VERSION 5.7 ;
  NOWIREEXTENSIONATPIN ON ;
  DIVIDERCHAR "/" ;
  BUSBITCHARS "[]" ;
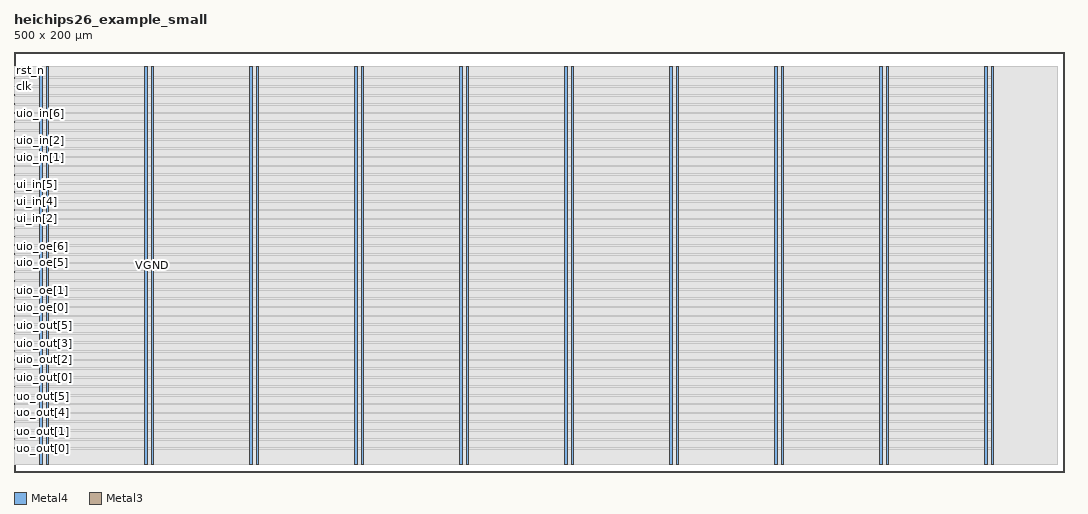
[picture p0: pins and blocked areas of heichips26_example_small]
MACRO heichips26_example_small
  CLASS BLOCK ;
  FOREIGN heichips26_example_small ;
  ORIGIN 0.000 0.000 ;
  SIZE 500.000 BY 200.000 ;
  PIN VGND
    DIRECTION INOUT ;
    USE GROUND ;
    PORT
      LAYER Metal4 ;
        RECT 15.380 3.560 16.380 193.000 ;
    END
    PORT
      LAYER Metal4 ;
        RECT 65.380 3.560 66.380 193.000 ;
    END
    PORT
      LAYER Metal4 ;
        RECT 115.380 3.560 116.380 193.000 ;
    END
    PORT
      LAYER Metal4 ;
        RECT 165.380 3.560 166.380 193.000 ;
    END
    PORT
      LAYER Metal4 ;
        RECT 215.380 3.560 216.380 193.000 ;
    END
    PORT
      LAYER Metal4 ;
        RECT 265.380 3.560 266.380 193.000 ;
    END
    PORT
      LAYER Metal4 ;
        RECT 315.380 3.560 316.380 193.000 ;
    END
    PORT
      LAYER Metal4 ;
        RECT 365.380 3.560 366.380 193.000 ;
    END
    PORT
      LAYER Metal4 ;
        RECT 415.380 3.560 416.380 193.000 ;
    END
    PORT
      LAYER Metal4 ;
        RECT 465.380 3.560 466.380 193.000 ;
    END
  END VGND
  PIN VPWR
    DIRECTION INOUT ;
    USE POWER ;
    PORT
      LAYER Metal4 ;
        RECT 12.380 3.560 13.380 193.000 ;
    END
    PORT
      LAYER Metal4 ;
        RECT 62.380 3.560 63.380 193.000 ;
    END
    PORT
      LAYER Metal4 ;
        RECT 112.380 3.560 113.380 193.000 ;
    END
    PORT
      LAYER Metal4 ;
        RECT 162.380 3.560 163.380 193.000 ;
    END
    PORT
      LAYER Metal4 ;
        RECT 212.380 3.560 213.380 193.000 ;
    END
    PORT
      LAYER Metal4 ;
        RECT 262.380 3.560 263.380 193.000 ;
    END
    PORT
      LAYER Metal4 ;
        RECT 312.380 3.560 313.380 193.000 ;
    END
    PORT
      LAYER Metal4 ;
        RECT 362.380 3.560 363.380 193.000 ;
    END
    PORT
      LAYER Metal4 ;
        RECT 412.380 3.560 413.380 193.000 ;
    END
    PORT
      LAYER Metal4 ;
        RECT 462.380 3.560 463.380 193.000 ;
    END
  END VPWR
  PIN clk
    DIRECTION INPUT ;
    USE SIGNAL ;
    PORT
      LAYER Metal3 ;
        RECT 0.000 183.340 0.400 183.740 ;
    END
  END clk
  PIN ena
    DIRECTION INPUT ;
    USE SIGNAL ;
    PORT
      LAYER Metal3 ;
        RECT 0.000 179.140 0.400 179.540 ;
    END
  END ena
  PIN rst_n
    DIRECTION INPUT ;
    USE SIGNAL ;
    PORT
      LAYER Metal3 ;
        RECT 0.000 187.540 0.400 187.940 ;
    END
  END rst_n
  PIN ui_in[0]
    DIRECTION INPUT ;
    USE SIGNAL ;
    ANTENNAGATEAREA 0.180700 ;
    PORT
      LAYER Metal3 ;
        RECT 0.000 111.940 0.400 112.340 ;
    END
  END ui_in[0]
  PIN ui_in[1]
    DIRECTION INPUT ;
    USE SIGNAL ;
    ANTENNAGATEAREA 0.180700 ;
    PORT
      LAYER Metal3 ;
        RECT 0.000 116.140 0.400 116.540 ;
    END
  END ui_in[1]
  PIN ui_in[2]
    DIRECTION INPUT ;
    USE SIGNAL ;
    ANTENNAGATEAREA 0.180700 ;
    PORT
      LAYER Metal3 ;
        RECT 0.000 120.340 0.400 120.740 ;
    END
  END ui_in[2]
  PIN ui_in[3]
    DIRECTION INPUT ;
    USE SIGNAL ;
    ANTENNAGATEAREA 0.180700 ;
    PORT
      LAYER Metal3 ;
        RECT 0.000 124.540 0.400 124.940 ;
    END
  END ui_in[3]
  PIN ui_in[4]
    DIRECTION INPUT ;
    USE SIGNAL ;
    ANTENNAGATEAREA 0.180700 ;
    PORT
      LAYER Metal3 ;
        RECT 0.000 128.740 0.400 129.140 ;
    END
  END ui_in[4]
  PIN ui_in[5]
    DIRECTION INPUT ;
    USE SIGNAL ;
    ANTENNAGATEAREA 0.180700 ;
    PORT
      LAYER Metal3 ;
        RECT 0.000 132.940 0.400 133.340 ;
    END
  END ui_in[5]
  PIN ui_in[6]
    DIRECTION INPUT ;
    USE SIGNAL ;
    ANTENNAGATEAREA 0.180700 ;
    PORT
      LAYER Metal3 ;
        RECT 0.000 137.140 0.400 137.540 ;
    END
  END ui_in[6]
  PIN ui_in[7]
    DIRECTION INPUT ;
    USE SIGNAL ;
    ANTENNAGATEAREA 0.180700 ;
    PORT
      LAYER Metal3 ;
        RECT 0.000 141.340 0.400 141.740 ;
    END
  END ui_in[7]
  PIN uio_in[0]
    DIRECTION INPUT ;
    USE SIGNAL ;
    ANTENNAGATEAREA 0.180700 ;
    PORT
      LAYER Metal3 ;
        RECT 0.000 145.540 0.400 145.940 ;
    END
  END uio_in[0]
  PIN uio_in[1]
    DIRECTION INPUT ;
    USE SIGNAL ;
    ANTENNAGATEAREA 0.180700 ;
    PORT
      LAYER Metal3 ;
        RECT 0.000 149.740 0.400 150.140 ;
    END
  END uio_in[1]
  PIN uio_in[2]
    DIRECTION INPUT ;
    USE SIGNAL ;
    ANTENNAGATEAREA 0.180700 ;
    PORT
      LAYER Metal3 ;
        RECT 0.000 153.940 0.400 154.340 ;
    END
  END uio_in[2]
  PIN uio_in[3]
    DIRECTION INPUT ;
    USE SIGNAL ;
    ANTENNAGATEAREA 0.180700 ;
    PORT
      LAYER Metal3 ;
        RECT 0.000 158.140 0.400 158.540 ;
    END
  END uio_in[3]
  PIN uio_in[4]
    DIRECTION INPUT ;
    USE SIGNAL ;
    ANTENNAGATEAREA 0.180700 ;
    PORT
      LAYER Metal3 ;
        RECT 0.000 162.340 0.400 162.740 ;
    END
  END uio_in[4]
  PIN uio_in[5]
    DIRECTION INPUT ;
    USE SIGNAL ;
    ANTENNAGATEAREA 0.180700 ;
    PORT
      LAYER Metal3 ;
        RECT 0.000 166.540 0.400 166.940 ;
    END
  END uio_in[5]
  PIN uio_in[6]
    DIRECTION INPUT ;
    USE SIGNAL ;
    ANTENNAGATEAREA 0.180700 ;
    PORT
      LAYER Metal3 ;
        RECT 0.000 170.740 0.400 171.140 ;
    END
  END uio_in[6]
  PIN uio_in[7]
    DIRECTION INPUT ;
    USE SIGNAL ;
    ANTENNAGATEAREA 0.180700 ;
    PORT
      LAYER Metal3 ;
        RECT 0.000 174.940 0.400 175.340 ;
    END
  END uio_in[7]
  PIN uio_oe[0]
    DIRECTION OUTPUT ;
    USE SIGNAL ;
    ANTENNADIFFAREA 0.299200 ;
    PORT
      LAYER Metal3 ;
        RECT 0.000 78.340 0.400 78.740 ;
    END
  END uio_oe[0]
  PIN uio_oe[1]
    DIRECTION OUTPUT ;
    USE SIGNAL ;
    ANTENNADIFFAREA 0.299200 ;
    PORT
      LAYER Metal3 ;
        RECT 0.000 82.540 0.400 82.940 ;
    END
  END uio_oe[1]
  PIN uio_oe[2]
    DIRECTION OUTPUT ;
    USE SIGNAL ;
    ANTENNADIFFAREA 0.299200 ;
    PORT
      LAYER Metal3 ;
        RECT 0.000 86.740 0.400 87.140 ;
    END
  END uio_oe[2]
  PIN uio_oe[3]
    DIRECTION OUTPUT ;
    USE SIGNAL ;
    ANTENNADIFFAREA 0.299200 ;
    PORT
      LAYER Metal3 ;
        RECT 0.000 90.940 0.400 91.340 ;
    END
  END uio_oe[3]
  PIN uio_oe[4]
    DIRECTION OUTPUT ;
    USE SIGNAL ;
    ANTENNADIFFAREA 0.299200 ;
    PORT
      LAYER Metal3 ;
        RECT 0.000 95.140 0.400 95.540 ;
    END
  END uio_oe[4]
  PIN uio_oe[5]
    DIRECTION OUTPUT ;
    USE SIGNAL ;
    ANTENNADIFFAREA 0.299200 ;
    PORT
      LAYER Metal3 ;
        RECT 0.000 99.340 0.400 99.740 ;
    END
  END uio_oe[5]
  PIN uio_oe[6]
    DIRECTION OUTPUT ;
    USE SIGNAL ;
    ANTENNADIFFAREA 0.299200 ;
    PORT
      LAYER Metal3 ;
        RECT 0.000 103.540 0.400 103.940 ;
    END
  END uio_oe[6]
  PIN uio_oe[7]
    DIRECTION OUTPUT ;
    USE SIGNAL ;
    ANTENNADIFFAREA 0.299200 ;
    PORT
      LAYER Metal3 ;
        RECT 0.000 107.740 0.400 108.140 ;
    END
  END uio_oe[7]
  PIN uio_out[0]
    DIRECTION OUTPUT ;
    USE SIGNAL ;
    ANTENNADIFFAREA 0.299200 ;
    PORT
      LAYER Metal3 ;
        RECT 0.000 44.740 0.400 45.140 ;
    END
  END uio_out[0]
  PIN uio_out[1]
    DIRECTION OUTPUT ;
    USE SIGNAL ;
    ANTENNADIFFAREA 0.299200 ;
    PORT
      LAYER Metal3 ;
        RECT 0.000 48.940 0.400 49.340 ;
    END
  END uio_out[1]
  PIN uio_out[2]
    DIRECTION OUTPUT ;
    USE SIGNAL ;
    ANTENNADIFFAREA 0.299200 ;
    PORT
      LAYER Metal3 ;
        RECT 0.000 53.140 0.400 53.540 ;
    END
  END uio_out[2]
  PIN uio_out[3]
    DIRECTION OUTPUT ;
    USE SIGNAL ;
    ANTENNADIFFAREA 0.299200 ;
    PORT
      LAYER Metal3 ;
        RECT 0.000 57.340 0.400 57.740 ;
    END
  END uio_out[3]
  PIN uio_out[4]
    DIRECTION OUTPUT ;
    USE SIGNAL ;
    ANTENNADIFFAREA 0.299200 ;
    PORT
      LAYER Metal3 ;
        RECT 0.000 61.540 0.400 61.940 ;
    END
  END uio_out[4]
  PIN uio_out[5]
    DIRECTION OUTPUT ;
    USE SIGNAL ;
    ANTENNADIFFAREA 0.299200 ;
    PORT
      LAYER Metal3 ;
        RECT 0.000 65.740 0.400 66.140 ;
    END
  END uio_out[5]
  PIN uio_out[6]
    DIRECTION OUTPUT ;
    USE SIGNAL ;
    ANTENNADIFFAREA 0.299200 ;
    PORT
      LAYER Metal3 ;
        RECT 0.000 69.940 0.400 70.340 ;
    END
  END uio_out[6]
  PIN uio_out[7]
    DIRECTION OUTPUT ;
    USE SIGNAL ;
    ANTENNADIFFAREA 0.299200 ;
    PORT
      LAYER Metal3 ;
        RECT 0.000 74.140 0.400 74.540 ;
    END
  END uio_out[7]
  PIN uo_out[0]
    DIRECTION OUTPUT ;
    USE SIGNAL ;
    ANTENNADIFFAREA 0.708600 ;
    PORT
      LAYER Metal3 ;
        RECT 0.000 11.140 0.400 11.540 ;
    END
  END uo_out[0]
  PIN uo_out[1]
    DIRECTION OUTPUT ;
    USE SIGNAL ;
    ANTENNADIFFAREA 0.708600 ;
    PORT
      LAYER Metal3 ;
        RECT 0.000 15.340 0.400 15.740 ;
    END
  END uo_out[1]
  PIN uo_out[2]
    DIRECTION OUTPUT ;
    USE SIGNAL ;
    ANTENNADIFFAREA 0.708600 ;
    PORT
      LAYER Metal3 ;
        RECT 0.000 19.540 0.400 19.940 ;
    END
  END uo_out[2]
  PIN uo_out[3]
    DIRECTION OUTPUT ;
    USE SIGNAL ;
    ANTENNADIFFAREA 0.708600 ;
    PORT
      LAYER Metal3 ;
        RECT 0.000 23.740 0.400 24.140 ;
    END
  END uo_out[3]
  PIN uo_out[4]
    DIRECTION OUTPUT ;
    USE SIGNAL ;
    ANTENNADIFFAREA 0.708600 ;
    PORT
      LAYER Metal3 ;
        RECT 0.000 27.940 0.400 28.340 ;
    END
  END uo_out[4]
  PIN uo_out[5]
    DIRECTION OUTPUT ;
    USE SIGNAL ;
    ANTENNADIFFAREA 0.708600 ;
    PORT
      LAYER Metal3 ;
        RECT 0.000 32.140 0.400 32.540 ;
    END
  END uo_out[5]
  PIN uo_out[6]
    DIRECTION OUTPUT ;
    USE SIGNAL ;
    ANTENNADIFFAREA 0.708600 ;
    PORT
      LAYER Metal3 ;
        RECT 0.000 36.340 0.400 36.740 ;
    END
  END uo_out[6]
  PIN uo_out[7]
    DIRECTION OUTPUT ;
    USE SIGNAL ;
    ANTENNADIFFAREA 0.708600 ;
    PORT
      LAYER Metal3 ;
        RECT 0.000 40.540 0.400 40.940 ;
    END
  END uo_out[7]
  OBS
      LAYER GatPoly ;
        RECT 2.880 3.630 496.800 192.930 ;
      LAYER Metal1 ;
        RECT 2.880 3.560 496.800 193.000 ;
      LAYER Metal2 ;
        RECT 2.295 3.635 466.185 192.925 ;
      LAYER Metal3 ;
        RECT 0.400 188.150 466.240 192.880 ;
        RECT 0.610 187.330 466.240 188.150 ;
        RECT 0.400 183.950 466.240 187.330 ;
        RECT 0.610 183.130 466.240 183.950 ;
        RECT 0.400 179.750 466.240 183.130 ;
        RECT 0.610 178.930 466.240 179.750 ;
        RECT 0.400 175.550 466.240 178.930 ;
        RECT 0.610 174.730 466.240 175.550 ;
        RECT 0.400 171.350 466.240 174.730 ;
        RECT 0.610 170.530 466.240 171.350 ;
        RECT 0.400 167.150 466.240 170.530 ;
        RECT 0.610 166.330 466.240 167.150 ;
        RECT 0.400 162.950 466.240 166.330 ;
        RECT 0.610 162.130 466.240 162.950 ;
        RECT 0.400 158.750 466.240 162.130 ;
        RECT 0.610 157.930 466.240 158.750 ;
        RECT 0.400 154.550 466.240 157.930 ;
        RECT 0.610 153.730 466.240 154.550 ;
        RECT 0.400 150.350 466.240 153.730 ;
        RECT 0.610 149.530 466.240 150.350 ;
        RECT 0.400 146.150 466.240 149.530 ;
        RECT 0.610 145.330 466.240 146.150 ;
        RECT 0.400 141.950 466.240 145.330 ;
        RECT 0.610 141.130 466.240 141.950 ;
        RECT 0.400 137.750 466.240 141.130 ;
        RECT 0.610 136.930 466.240 137.750 ;
        RECT 0.400 133.550 466.240 136.930 ;
        RECT 0.610 132.730 466.240 133.550 ;
        RECT 0.400 129.350 466.240 132.730 ;
        RECT 0.610 128.530 466.240 129.350 ;
        RECT 0.400 125.150 466.240 128.530 ;
        RECT 0.610 124.330 466.240 125.150 ;
        RECT 0.400 120.950 466.240 124.330 ;
        RECT 0.610 120.130 466.240 120.950 ;
        RECT 0.400 116.750 466.240 120.130 ;
        RECT 0.610 115.930 466.240 116.750 ;
        RECT 0.400 112.550 466.240 115.930 ;
        RECT 0.610 111.730 466.240 112.550 ;
        RECT 0.400 108.350 466.240 111.730 ;
        RECT 0.610 107.530 466.240 108.350 ;
        RECT 0.400 104.150 466.240 107.530 ;
        RECT 0.610 103.330 466.240 104.150 ;
        RECT 0.400 99.950 466.240 103.330 ;
        RECT 0.610 99.130 466.240 99.950 ;
        RECT 0.400 95.750 466.240 99.130 ;
        RECT 0.610 94.930 466.240 95.750 ;
        RECT 0.400 91.550 466.240 94.930 ;
        RECT 0.610 90.730 466.240 91.550 ;
        RECT 0.400 87.350 466.240 90.730 ;
        RECT 0.610 86.530 466.240 87.350 ;
        RECT 0.400 83.150 466.240 86.530 ;
        RECT 0.610 82.330 466.240 83.150 ;
        RECT 0.400 78.950 466.240 82.330 ;
        RECT 0.610 78.130 466.240 78.950 ;
        RECT 0.400 74.750 466.240 78.130 ;
        RECT 0.610 73.930 466.240 74.750 ;
        RECT 0.400 70.550 466.240 73.930 ;
        RECT 0.610 69.730 466.240 70.550 ;
        RECT 0.400 66.350 466.240 69.730 ;
        RECT 0.610 65.530 466.240 66.350 ;
        RECT 0.400 62.150 466.240 65.530 ;
        RECT 0.610 61.330 466.240 62.150 ;
        RECT 0.400 57.950 466.240 61.330 ;
        RECT 0.610 57.130 466.240 57.950 ;
        RECT 0.400 53.750 466.240 57.130 ;
        RECT 0.610 52.930 466.240 53.750 ;
        RECT 0.400 49.550 466.240 52.930 ;
        RECT 0.610 48.730 466.240 49.550 ;
        RECT 0.400 45.350 466.240 48.730 ;
        RECT 0.610 44.530 466.240 45.350 ;
        RECT 0.400 41.150 466.240 44.530 ;
        RECT 0.610 40.330 466.240 41.150 ;
        RECT 0.400 36.950 466.240 40.330 ;
        RECT 0.610 36.130 466.240 36.950 ;
        RECT 0.400 32.750 466.240 36.130 ;
        RECT 0.610 31.930 466.240 32.750 ;
        RECT 0.400 28.550 466.240 31.930 ;
        RECT 0.610 27.730 466.240 28.550 ;
        RECT 0.400 24.350 466.240 27.730 ;
        RECT 0.610 23.530 466.240 24.350 ;
        RECT 0.400 20.150 466.240 23.530 ;
        RECT 0.610 19.330 466.240 20.150 ;
        RECT 0.400 15.950 466.240 19.330 ;
        RECT 0.610 15.130 466.240 15.950 ;
        RECT 0.400 11.750 466.240 15.130 ;
        RECT 0.610 10.930 466.240 11.750 ;
        RECT 0.400 3.680 466.240 10.930 ;
  END
END heichips26_example_small
END LIBRARY

